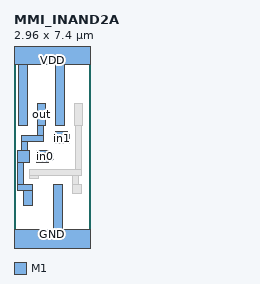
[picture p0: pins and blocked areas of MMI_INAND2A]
MACRO MMI_INAND2A
	CLASS CORE ;
	FOREIGN MMI_INAND2A 0 0 ;
	SIZE 2.96 BY 7.4 ;
	SYMMETRY X Y ;
	SITE CORE1 ;
	PIN out
		DIRECTION output ;
		USE SIGNAL ;
		PORT
			LAYER M1 ;
			RECT 0.9 4.55 1.24 5.39 ;
			LAYER M1 ;
			RECT 0.9 4.135 1.13 4.55 ;
			LAYER M1 ;
			RECT 0.29 3.905 1.13 4.135 ;
			LAYER M1 ;
			RECT 0.29 3.555 0.52 3.905 ;
			LAYER M1 ;
			RECT 0.145 3.08 0.595 3.555 ;
			LAYER M1 ;
			RECT 0.145 2.255 0.375 3.08 ;
			LAYER M1 ;
			RECT 0.145 2.025 0.72 2.255 ;
			LAYER M1 ;
			RECT 0.38 1.415 0.72 2.025 ;
		END
		AntennaDiffArea 0.9384 ;
	END out
	PIN in1
		DIRECTION input ;
		USE SIGNAL ;
		PORT
			LAYER M1 ;
			RECT 1.625 4.19 2.075 4.295 ;
			LAYER M1 ;
			RECT 1.625 3.85 2.15 4.19 ;
			LAYER M1 ;
			RECT 1.625 3.845 2.075 3.85 ;
		END
		AntennaGateArea 0.2484 ;
	END in1
	PIN GND
		DIRECTION inout ;
		USE GROUND ;
		PORT
			LAYER M1 ;
			RECT 1.53 0.5 1.87 2.255 ;
			LAYER M1 ;
			RECT 0 -0.5 2.96 0.5 ;
		END
	END GND
	PIN VDD
		DIRECTION inout ;
		USE POWER ;
		PORT
			LAYER M1 ;
			RECT 0 6.9 2.96 7.9 ;
			LAYER M1 ;
			RECT 0.18 4.55 0.52 6.9 ;
			LAYER M1 ;
			RECT 1.62 4.55 1.96 6.9 ;
		END
	END VDD
	PIN in0
		DIRECTION input ;
		USE SIGNAL ;
		PORT
			LAYER M1 ;
			RECT 0.885 3.5 1.335 3.555 ;
			LAYER M1 ;
			RECT 0.885 3.445 1.48 3.5 ;
			LAYER M1 ;
			RECT 0.885 3.215 1.545 3.445 ;
			LAYER M1 ;
			RECT 0.885 3.16 1.48 3.215 ;
			LAYER M1 ;
			RECT 0.885 3.105 1.335 3.16 ;
		END
		AntennaGateArea 0.3312 ;
	END in0
	OBS
		LAYER M1 ;
		RECT 2.34 4.55 2.68 5.39 ;
		LAYER M1 ;
		RECT 2.395 2.83 2.625 4.55 ;
		LAYER M1 ;
		RECT 0.62 2.6 2.625 2.83 ;
		LAYER M1 ;
		RECT 0.62 2.49 0.96 2.6 ;
		LAYER M1 ;
		RECT 2.29 2.255 2.52 2.6 ;
		LAYER M1 ;
		RECT 2.29 1.875 2.63 2.255 ;
	END
END MMI_INAND2A
